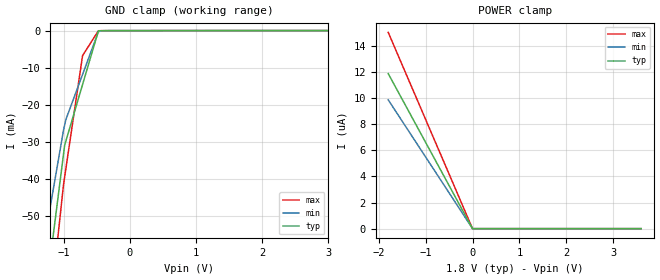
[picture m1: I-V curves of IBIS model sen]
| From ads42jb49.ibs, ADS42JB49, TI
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|   sen Model
[Model]   sen
Model_type   Input
Vinl = 0.4
Vinh = 1.2
|   typ   min   max
|   (nom PVT)   (fast PVT)   (slow PVT)
C_comp   1.286e-12   1.247e-12   1.328e-12
| Where nom  PVT is Nominal Process, 1.8V, 25C
|   Fast PVT is Strong Process,  1.9V, -40C
|   Slow PVT is Weak Process,   1.7V, 125C
[Voltage Range]   1.8   1.7   1.9
|Junction Temperature
[Temperature Range]   25   125   -40
[Power Clamp Reference]   1.8   1.7   1.9
[GND Clamp Reference]   0   0   0
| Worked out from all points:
|   GND clamp passes 1 mA (typ) near -0.49 V on its own axis
[GND Clamp]
|   Voltage   I(typ)   I(min)   I(max)
-1.8V     -820.9mA   -109.7mA   -1.727A
-1.49V    -102.4mA   -77.57mA   -123.3mA
-1.001V   -33.56mA   -27.01mA   -41.82mA
-982.8mV  -30.95mA   -25.49mA   -39.53mA
-965.6mV  -29.91mA   -24.08mA   -37.44mA
-712.5mV  -14.58mA   -11.87mA   -6.77mA
-473.1mV  -87.82uA   -310.1uA   -47uA
-280.5mV  -14.2uA    -14.49uA   -18.27uA
3.6V      0A         0A         0A
[POWER Clamp]
|   Voltage   I(typ)   I(min)   I(max)
-1.8V     11.89uA    9.877uA    15.05uA
-1.7mV    11.25nA    11.26nA    14.23nA
0V        0A         0A         0A
3.6V      0A         0A         0A
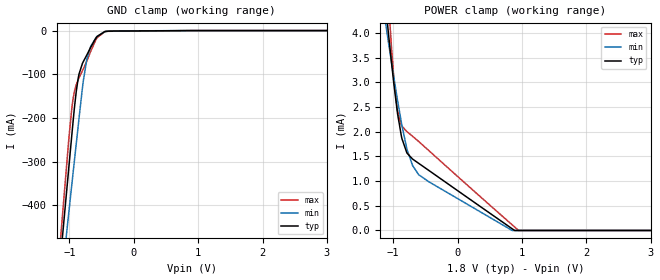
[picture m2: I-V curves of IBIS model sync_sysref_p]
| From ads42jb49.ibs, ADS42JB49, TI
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|   sync_sysref Model
[Model]   sync_sysref_p
Model_type   Input
Vinl = 0.5
Vinh = 1.3
|   typ   min   max
|   (nom PVT)   (fast PVT)   (slow PVT)
C_comp   1.431e-12   1.371e-12   1.487e-12
| Where nom  PVT is Nominal Process, 1.8V, 25C
|   Fast PVT is Strong Process,  1.9V, -40C
|   Slow PVT is Weak Process,   1.7V, 125C
[Voltage Range]   1.8   1.7   1.9
|Junction Temperature
[Temperature Range]   25   125   -40
[Power Clamp Reference]   1.8   1.7   1.9
[GND Clamp Reference]   0   0   0
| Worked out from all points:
|   GND clamp passes 1 mA (typ) near -0.18 V on its own axis
|   POWER clamp passes 1 mA (typ) near -0.21 V on its own axis
[GND Clamp]
|   Voltage   I(typ)   I(min)   I(max)
-1.8V     -1.605A    -1.53A     -1.676A
-1.195V   -611.2mA   -672.5mA   -577.9mA
-1.01V    -314mA     -416.5mA   -249.1mA
-941.4mV  -205.8mA   -323.5mA   -155mA
-894.6mV  -140.7mA   -260.2mA   -124.3mA
-863.3mV  -109.2mA   -218mA     -112.3mA
-786.8mV  -71.87mA   -118.2mA   -88.8mA
-730.7mV  -56.24mA   -66.69mA   -70.32mA
-669.5mV  -38.22mA   -36.27mA   -47.63mA
-586.8mV  -16.99mA   -16.1mA    -20.59mA
-450mV    -2.211mA   -2.6mA     -2.479mA
3.6V      0A         0A         0A
[POWER Clamp]
|   Voltage   I(typ)   I(min)   I(max)
-1.8V     13.87mA    10.45mA    22.16mA
-1.177V   5.343mA    4.728mA    7.007mA
-1.07V    3.957mA    3.791mA    4.608mA
-1.028V   3.429mA    3.426mA    3.747mA
-987.4mV  2.954mA    3.087mA    3.05mA
-929.6mV  2.351mA    2.62mA     2.41mA
-864mV    1.864mA    2.129mA    2.114mA
-788.4mV  1.578mA    1.664mA    2.006mA
-604.9mV  1.362mA    1.132mA    1.805mA
848.6mV   34.76uA    392.2nA    115uA
953.1mV   0A         0A         0A
3.6V      0A         0A         0A
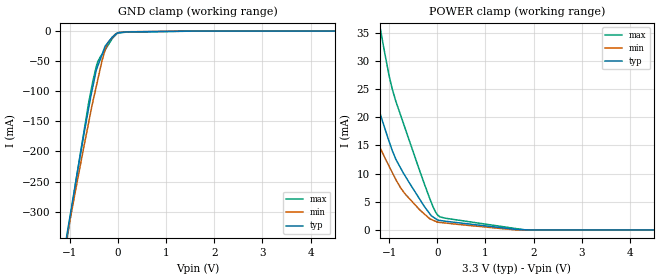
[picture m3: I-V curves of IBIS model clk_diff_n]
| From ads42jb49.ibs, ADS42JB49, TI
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[Model]   clk_diff_n
Model_type   Input
Vinl = 0.99
Vinh = 2.31
|   (nom PVT)   (fast PVT)   (slow PVT)
 C_comp   1.978e-12   1.903e-12   2.058e-12
|Where  nom  PVT is Nominal Process, 3.3V, 25C
|   Fast PVT is Strong Process,  3.45V, -40C
|   Slow PVT is Weak Process,   3.15V, 125C
[Model spec]
|subparameter   typ   min   max
Vinl   0.99   0.945   1.035
Vinh   2.31   2.205   2.415
[Voltage Range]   3.3   3.15   3.45
|Junction Temperature
[Temperature Range]   25   125   -40
[Power Clamp Reference]   3.3   3.15   3.45
[GND Clamp Reference]   0   0   0
[GND Clamp]
|   Voltage   I(typ)   I(min)   I(max)
-3.3V     -1.785A    -1.645A    -1.893A
-1.518V   -555.1mA   -536.1mA   -582.8mA
-861.3mV  -240.5mA   -254.1mA   -240.7mA
-621mV    -131.5mA   -155mA     -122.6mA
-527.9mV  -92.85mA   -117.9mA   -83.7mA
-452mV    -64.25mA   -90.76mA   -57.98mA
-333.9mV  -38.69mA   -48.81mA   -38.45mA
-270.6mV  -24.98mA   -31.29mA   -31.21mA
-211mV    -18.93mA   -19.15mA   -23.69mA
-113.9mV  -9.365mA   -10.17mA   -11.41mA
-39.41fV  -2.687mA   -2.734mA   -3.197mA
6.6V      0A         0A         0A
[POWER Clamp]
|   Voltage   I(typ)   I(min)   I(max)
-3.3V     78.93mA    53.76mA    139.8mA
-3.15V    74.76mA    50.97mA    132.4mA
-1.98V    42.25mA    29.17mA    74.55mA
-1.832V   38.17mA    26.41mA    67.23mA
-1.499V   29.02mA    20.22mA    50.98mA
-1.232V   21.76mA    15.33mA    37.9mA
-1.093V   18.07mA    12.85mA    31.37mA
-861.3mV  12.54mA    8.911mA    22.82mA
-365.4mV  5.451mA    3.563mA    10.48mA
-3.15mV   1.81mA     1.415mA    2.75mA
1.839V    32.5uA     0A         0A
6.6V      0A         0A         0A
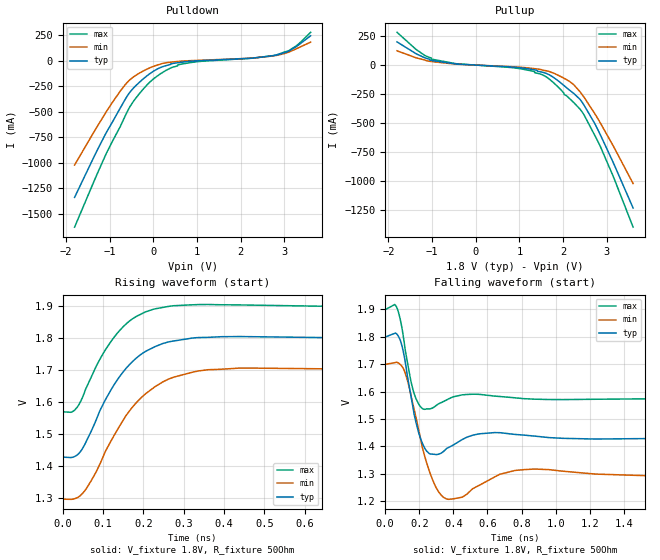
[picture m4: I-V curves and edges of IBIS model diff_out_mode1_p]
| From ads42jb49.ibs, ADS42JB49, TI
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|   diff_out_mode1 Model
[Model]   diff_out_mode1_p
Model_type   Output
Polarity   Non-Inverting
Vmeas = 1.622
Vref = 1.8
Cref = 0.5pF
Rref = 50
|   typ   min   max
|   (nom PVT)   (fast PVT)   (slow PVT)
C_comp   2.796e-12   2.332e-12   2.950e-12
[Model spec]
|subparameter   typ   min   max
Vmeas   1.622   1.52   1.7368
| Where nom  PVT is Nominal Process, 1.8V, 25C
|   Fast PVT is Strong Process,  1.9V, -40C
|   Slow PVT is Weak Process,   1.7V, 125C
[Voltage Range]   1.8   1.7   1.9
|Junction Temperature
[Temperature Range]   25   125   -40
[Pullup Reference]   1.8   1.7   1.9
[Pulldown Reference]   0   0   0
[Power Clamp Reference]   1.8   1.7   1.9
[GND Clamp Reference]   0   0   0
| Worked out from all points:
|   slope of the pulldown table from 0 to 0.27 V, typ, clamps not added: 5.06 ohm
|   slope of the pullup table from 0 to 0.27 V, typ, clamps not added: 49.4 ohm
|   falling waveform, V_fixture 1.8V, R_fixture 50Ohm: 20-80 % time 62.5ps typ, 86.6ps min, 53.8ps max; typ from 1.8 V to 1.43 V
|   rising waveform, V_fixture 1.8V, R_fixture 50Ohm: 20-80 % time 104ps typ, 118ps min, 93.6ps max; typ from 1.43 V to 1.8 V
[Pulldown]
|   Voltage   I(typ)   I(min)   I(max)
-1.8V     -1.339A    -1.022A    -1.631A
-1.084V   -711.4mA   -506.3mA   -917.2mA
-619.2mV  -362.5mA   -223.9mA   -520.4mA
-373.1mV  -233.8mA   -136mA     -352.5mA
-1.4mV    -104.7mA   -56.4mA    -180.4mA
316.5mV   -45.53mA   -18.59mA   -88.86mA
621mV     -16.47mA   -5.382mA   -35.66mA
2.252V    24.47mA    25mA       24.07mA
2.821V    55.2mA     51.92mA    56.97mA
3.103V    95.45mA    84.7mA     99.44mA
3.265V    136.7mA    115.3mA    143.4mA
3.6V      244.5mA    181.9mA    278mA
[Pullup]
|   Voltage   I(typ)   I(min)   I(max)
-1.8V     200.2mA    123.4mA    282.9mA
-1.352V   95.72mA    61.49mA    131.8mA
-1.015V   39.9mA     30.23mA    51.76mA
-450mV    9.4mA      7.851mA    11.89mA
1.082V    -26.42mA   -20.42mA   -36.05mA
1.345V    -41.54mA   -30.87mA   -56.55mA
1.694V    -86.38mA   -57.15mA   -124.5mA
2.154V    -218.9mA   -143.6mA   -291.8mA
2.475V    -344.9mA   -276.5mA   -428.6mA
2.842V    -595.7mA   -494.2mA   -695.6mA
3.172V    -864.6mA   -717mA     -986.8mA
3.6V      -1.235A    -1.023A    -1.4A
[Ramp]
R_load = 50
|   typ   min   max
dV/dt_r   0.100221/5.88979e-11   0.132023/7.44432e-11  0.0812183/4.87785e-11
dV/dt_f   0.223044/6.23591e-11   0.242156/8.6598e-11   0.197134/5.3486e-11
[Falling Waveform]
V_fixture = 1.8V
V_fixture_min = 1.7V
V_fixture_max = 1.9V
R_fixture = 50Ohm
|   Time   V(typ)   V(min)   V(max)
0s        1.799V     1.699V     1.899V
56ps      1.813V     1.706V     1.918V
92ps      1.781V     1.697V     1.852V
150ps     1.588V     1.589V     1.64V
202ps     1.439V     1.444V     1.549V
276ps     1.372V     1.281V     1.54V
360ps     1.392V     1.208V     1.57V
552ps     1.446V     1.258V     1.59V
812ps     1.441V     1.315V     1.574V
2.198ns   1.428V     1.296V     1.571V
[Rising Waveform]
V_fixture = 1.8V
V_fixture_min = 1.7V
V_fixture_max = 1.9V
R_fixture = 50Ohm
|   Time   V(typ)   V(min)   V(max)
0s        1.427V     1.295V     1.568V
30ps      1.429V     1.297V     1.574V
54ps      1.465V     1.321V     1.629V
108ps     1.611V     1.45V      1.766V
166ps     1.716V     1.572V     1.852V
200ps     1.753V     1.618V     1.877V
248ps     1.781V     1.661V     1.894V
336ps     1.8V       1.695V     1.903V
444ps     1.803V     1.705V     1.902V
1.8ns     1.798V     1.698V     1.899V
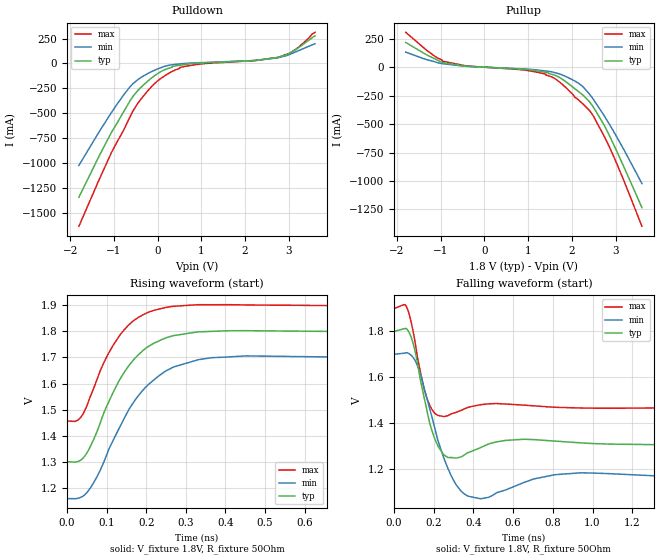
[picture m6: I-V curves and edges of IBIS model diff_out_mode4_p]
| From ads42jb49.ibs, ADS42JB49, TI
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|   diff_out_mode4 Model
[Model]   diff_out_mode4_p
Model_type   Output
Polarity   Non-Inverting
Vmeas = 1.565
Vref = 1.8
Cref = 0.5pF
Rref = 50
|   typ   min   max
|   (nom PVT)   (fast PVT)   (slow PVT)
C_comp   2.863e-12   2.367e-12   2.927e-12
[Model spec]
|subparameter   typ   min   max
Vmeas   1.565   1.465   1.685
| Where nom  PVT is Nominal Process, 1.8V, 25C
|   Fast PVT is Strong Process,  1.9V, -40C
|   Slow PVT is Weak Process,   1.7V, 125C
[Voltage Range]   1.8   1.7   1.9
|Junction Temperature
[Temperature Range]   25   125   -40
[Pullup Reference]   1.8   1.7   1.9
[Pulldown Reference]   0   0   0
[Power Clamp Reference]   1.8   1.7   1.9
[GND Clamp Reference]   0   0   0
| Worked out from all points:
|   slope of the pulldown table from 0 to 0.27 V, typ, clamps not added: 4.87 ohm
|   slope of the pullup table from 0 to 0.27 V, typ, clamps not added: 49.4 ohm
|   falling waveform, V_fixture 1.8V, R_fixture 50Ohm: 20-80 % time 69.6ps typ, 102ps min, 58.2ps max; typ from 1.8 V to 1.3 V
|   rising waveform, V_fixture 1.8V, R_fixture 50Ohm: 20-80 % time 102ps typ, 118ps min, 89.8ps max; typ from 1.3 V to 1.8 V
[Pulldown]
|   Voltage   I(typ)   I(min)   I(max)
-1.8V     -1.343A    -1.024A    -1.634A
-1.061V   -696.1mA   -496.5mA   -899.3mA
-783.5mV  -490.1mA   -320.6mA   -676mA
-610.2mV  -361.6mA   -224.8mA   -516.5mA
-373.1mV  -237mA     -139.3mA   -354.3mA
300uV     -101.9mA   -55.32mA   -175mA
333mV     -32.43mA   -13.29mA   -80.31mA
621mV     -11.39mA   -473.8uA   -30.46mA
2.252V    30.35mA    30.89mA    29.39mA
2.819V    72.47mA    63.9mA     67.36mA
3.173V    142.9mA    118.6mA    146.2mA
3.6V      277mA      197.8mA    312.4mA
[Pullup]
|   Voltage   I(typ)   I(min)   I(max)
-1.8V     217.1mA    132.2mA    306.5mA
-1.298V   103.6mA    63.77mA    141.1mA
-965.9mV  42.1mA     30.98mA    53.78mA
-450mV    10.25mA    8.157mA    13.33mA
1.082V    -26.37mA   -20.4mA    -35.98mA
1.397V    -44.75mA   -33.18mA   -60.73mA
1.722V    -92.16mA   -60.25mA   -132.7mA
2.154V    -215.6mA   -142.1mA   -289.1mA
2.493V    -352.2mA   -284.3mA   -431.1mA
2.732V    -506.6mA   -423.6mA   -603.8mA
2.911V    -644.8mA   -536.9mA   -746.5mA
3.6V      -1.234A    -1.023A    -1.398A
[Ramp]
R_load = 50
|   typ   min   max
dV/dt_r   0.119586/5.97826e-11   0.156071/7.40423e-11  0.0970831/4.79799e-11
dV/dt_f   0.297703/6.94567e-11   0.322276/1.01522e-10   0.263138/5.8084e-11
[Falling Waveform]
V_fixture = 1.8V
V_fixture_min = 1.7V
V_fixture_max = 1.9V
R_fixture = 50Ohm
|   Time   V(typ)   V(min)   V(max)
0s        1.799V     1.699V     1.899V
56ps      1.812V     1.705V     1.916V
86ps      1.776V     1.696V     1.842V
152ps     1.511V     1.551V     1.548V
202ps     1.338V     1.389V     1.445V
290ps     1.248V     1.165V     1.44V
376ps     1.27V      1.079V     1.468V
562ps     1.323V     1.106V     1.482V
940ps     1.312V     1.181V     1.465V
2.3ns     1.303V     1.162V     1.461V
[Rising Waveform]
V_fixture = 1.8V
V_fixture_min = 1.7V
V_fixture_max = 1.9V
R_fixture = 50Ohm
|   Time   V(typ)   V(min)   V(max)
0s        1.303V     1.162V     1.458V
34ps      1.308V     1.166V     1.471V
58ps      1.358V     1.2V       1.548V
108ps     1.54V      1.358V     1.725V
162ps     1.681V     1.516V     1.833V
198ps     1.734V     1.586V     1.868V
246ps     1.773V     1.645V     1.89V
334ps     1.798V     1.692V     1.902V
454ps     1.802V     1.706V     1.9V
1.8ns     1.799V     1.699V     1.899V
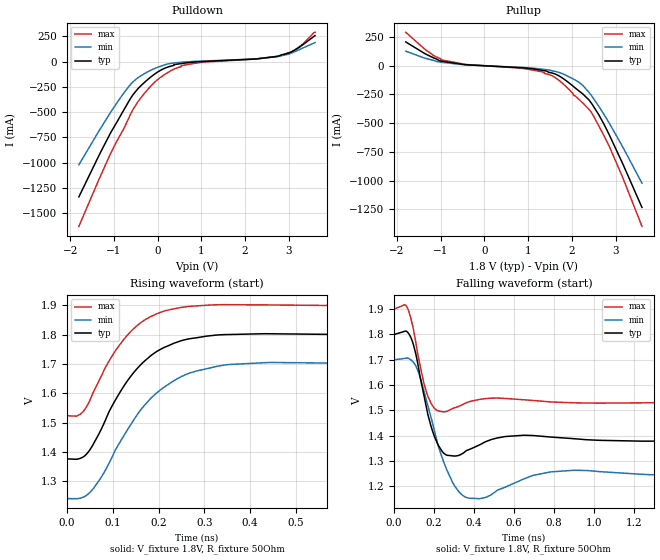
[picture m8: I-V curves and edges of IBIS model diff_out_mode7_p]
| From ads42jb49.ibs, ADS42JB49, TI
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|   diff_out_mode7 Model
[Model]   diff_out_mode7_p
Model_type   Output
Polarity   Non-Inverting
Vmeas = 1.599
Vref = 1.8
Cref = 0.5pF
Rref = 50
|   typ   min   max
|   (nom PVT)   (fast PVT)   (slow PVT)
C_comp   2.815e-12   2.354e-12   2.818e-12
[Model spec]
|subparameter   typ   min   max
Vmeas   1.599   1.498   1.7186
| Where nom  PVT is Nominal Process, 1.8V, 25C
|   Fast PVT is Strong Process,  1.9V, -40C
|   Slow PVT is Weak Process,   1.7V, 125C
[Voltage Range]   1.8   1.7   1.9
|Junction Temperature
[Temperature Range]   25   125   -40
[Pullup Reference]   1.8   1.7   1.9
[Pulldown Reference]   0   0   0
[Power Clamp Reference]   1.8   1.7   1.9
[GND Clamp Reference]   0   0   0
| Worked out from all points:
|   slope of the pulldown table from 0 to 0.27 V, typ, clamps not added: 4.97 ohm
|   slope of the pullup table from 0 to 0.27 V, typ, clamps not added: 49.4 ohm
|   falling waveform, V_fixture 1.8V, R_fixture 50Ohm: 20-80 % time 65.5ps typ, 93ps min, 55.6ps max; typ from 1.8 V to 1.38 V
|   rising waveform, V_fixture 1.8V, R_fixture 50Ohm: 20-80 % time 103ps typ, 118ps min, 91.9ps max; typ from 1.38 V to 1.8 V
[Pulldown]
|   Voltage   I(typ)   I(min)   I(max)
-1.8V     -1.341A    -1.023A    -1.632A
-1.082V   -711.8mA   -507.4mA   -917.2mA
-617.4mV  -363.6mA   -225.3mA   -521mA
-373.1mV  -235.1mA   -137.4mA   -353.4mA
20.08fV   -103.3mA   -55.85mA   -178.1mA
369mV     -31.78mA   -13.84mA   -75.35mA
621mV     -14.43mA   -3.408mA   -33.58mA
2.252V    26.68mA    27.26mA    26.11mA
2.842V    68.11mA    59.78mA    62.8mA
3.019V    88.51mA    78.83mA    91.79mA
3.229V    139.5mA    116.9mA    143.3mA
3.6V      257.6mA    188.7mA    290.9mA
[Pullup]
|   Voltage   I(typ)   I(min)   I(max)
-1.8V     207.4mA    127mA      291.5mA
-1.334V   99.81mA    62.88mA    135.5mA
-998.2mV  40.88mA    30.65mA    52.3mA
-450mV    9.603mA    7.918mA    12.22mA
1.082V    -26.4mA    -20.41mA   -36.03mA
1.364V    -42.72mA   -31.72mA   -58.17mA
1.7V      -87.57mA   -57.74mA   -126.2mA
2.154V    -217.5mA   -143mA     -290.8mA
2.479V    -345.6mA   -277.7mA   -427.8mA
2.858V    -606mA     -503.7mA   -706.3mA
3.18V     -870.3mA   -721.2mA   -992.5mA
3.6V      -1.234A    -1.023A    -1.399A
[Ramp]
R_load = 50
|   typ   min   max
dV/dt_r   0.108423/5.8938e-11   0.142735/7.37867e-11  0.0879367/4.77709e-11
dV/dt_f   0.252793/6.51883e-11   0.274288/9.27035e-11   0.223268/5.55748e-11
[Falling Waveform]
V_fixture = 1.8V
V_fixture_min = 1.7V
V_fixture_max = 1.9V
R_fixture = 50Ohm
|   Time   V(typ)   V(min)   V(max)
0s        1.799V     1.699V     1.899V
54ps      1.812V     1.705V     1.917V
86ps      1.785V     1.699V     1.859V
152ps     1.552V     1.57V      1.6V
200ps     1.402V     1.428V     1.51V
262ps     1.324V     1.27V      1.495V
362ps     1.341V     1.156V     1.53V
558ps     1.397V     1.197V     1.547V
902ps     1.388V     1.263V     1.53V
2.258ns   1.378V     1.242V     1.527V
[Rising Waveform]
V_fixture = 1.8V
V_fixture_min = 1.7V
V_fixture_max = 1.9V
R_fixture = 50Ohm
|   Time   V(typ)   V(min)   V(max)
0s        1.377V     1.242V     1.524V
32ps      1.381V     1.244V     1.533V
56ps      1.423V     1.273V     1.599V
80ps      1.495V     1.328V     1.676V
106ps     1.578V     1.408V     1.746V
162ps     1.699V     1.546V     1.842V
234ps     1.771V     1.644V     1.888V
326ps     1.799V     1.692V     1.902V
446ps     1.803V     1.705V     1.901V
1.4ns     1.798V     1.698V     1.899V
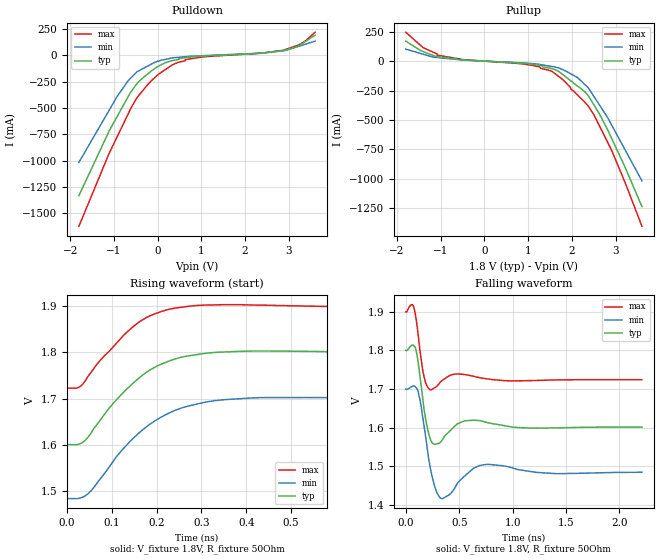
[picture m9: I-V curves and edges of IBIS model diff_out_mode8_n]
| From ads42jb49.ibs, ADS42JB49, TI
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[Model]   diff_out_mode8_n
Model_type   Output
Polarity   Non-Inverting
Vmeas = 1.707
Vref = 1.8
Cref = 0.5pF
Rref = 50
|   typ   min   max
|   (nom PVT)   (fast PVT)   (slow PVT)
C_comp   2.522e-12   2.302e-12   2.751e-12
[Model spec]
|subparameter   typ   min   max
Vmeas   1.707   1.606   1.806
| Where nom  PVT is Nominal Process, 1.8V, 25C
|   Fast PVT is Strong Process,  1.9V, -40C
|   Slow PVT is Weak Process,   1.7V, 125C
[Voltage Range]   1.8   1.7   1.9
[Temperature Range]   25   125   -40
[Pullup Reference]   1.8   1.7   1.9
[Pulldown Reference]   0   0   0
[Power Clamp Reference]   1.8   1.7   1.9
[GND Clamp Reference]   0   0   0
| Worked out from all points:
|   slope of the pulldown table from 0 to 0.27 V, typ, clamps not added: 5.4 ohm
|   slope of the pullup table from 0 to 0.27 V, typ, clamps not added: 49.4 ohm
|   falling waveform, V_fixture 1.8V, R_fixture 50Ohm: 20-80 % time 54.5ps typ, 67.2ps min, 47.9ps max; typ from 1.8 V to 1.6 V
|   rising waveform, V_fixture 1.8V, R_fixture 50Ohm: 20-80 % time 117ps typ, 128ps min, 103ps max; typ from 1.6 V to 1.8 V
[Pulldown]
|   Voltage   I(typ)   I(min)   I(max)
-1.8V     -1.332A    -1.017A    -1.623A
-1.11V    -720.8mA   -522.6mA   -932.2mA
-921.4mV  -578.2mA   -388mA     -770.1mA
-630mV    -360.2mA   -221.7mA   -519.2mA
-473.1mV  -269.2mA   -156.7mA   -403.7mA
-231.8mV  -178.3mA   -103.2mA   -280.4mA
11.97fV   -108.2mA   -57.48mA   -187.2mA
334.4mV   -50.6mA    -24.8mA    -91.31mA
632.7mV   -23.1mA    -13.1mA    -42.24mA
2.867V    45.49mA    43.39mA    47.29mA
3.213V    87.17mA    83.77mA    95.24mA
3.6V      191.1mA    134.1mA    218.5mA
[Pullup]
|   Voltage   I(typ)   I(min)   I(max)
-1.8V     170mA      102.2mA    245.2mA
-1.406V   81.95mA    59.19mA    115.2mA
-1.081V   39.54mA    30.23mA    50.84mA
-473.1mV  9.778mA    8.239mA    12.23mA
1.146V    -30.52mA   -23.01mA   -40.64mA
1.55V     -64.36mA   -45.45mA   -88.57mA
1.796V    -115.5mA   -73.12mA   -158.8mA
2.125V    -211.8mA   -139.3mA   -287mA
2.362V    -288.7mA   -222.8mA   -377.8mA
2.5V      -370.3mA   -299.4mA   -455.3mA
2.905V    -654.6mA   -541.9mA   -757mA
3.6V      -1.237A    -1.018A    -1.404A
[Ramp]
R_load = 50
|   typ   min   max
dV/dt_r   0.0649191/7.51387e-11  0.0842193/9.2168e-11   0.0524826/6.48584e-11
dV/dt_f   0.118972/5.40691e-11   0.129264/6.71371e-11   0.105444/4.76743e-11
[Falling Waveform]
V_fixture = 1.8V
V_fixture_min = 1.7V
V_fixture_max = 1.9V
R_fixture = 50Ohm
|   Time   V(typ)   V(min)   V(max)
0s        1.8V       1.7V       1.9V
64ps      1.814V     1.708V     1.918V
112ps     1.777V     1.696V     1.85V
166ps     1.659V     1.613V     1.738V
216ps     1.583V     1.516V     1.701V
274ps     1.557V     1.445V     1.704V
338ps     1.567V     1.416V     1.722V
550ps     1.618V     1.474V     1.738V
760ps     1.613V     1.505V     1.726V
2.21ns    1.601V     1.484V     1.724V
[Rising Waveform]
V_fixture = 1.8V
V_fixture_min = 1.7V
V_fixture_max = 1.9V
R_fixture = 50Ohm
|   Time   V(typ)   V(min)   V(max)
0s        1.601V     1.484V     1.723V
26ps      1.601V     1.484V     1.724V
48ps      1.618V     1.495V     1.75V
110ps     1.697V     1.574V     1.82V
144ps     1.73V      1.61V      1.853V
178ps     1.758V     1.64V      1.876V
242ps     1.786V     1.675V     1.896V
328ps     1.8V       1.695V     1.903V
442ps     1.803V     1.702V     1.902V
2ns       1.799V     1.699V     1.899V
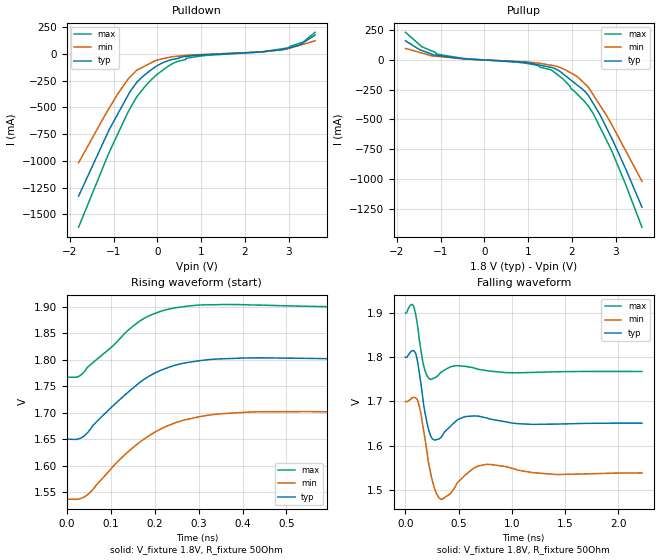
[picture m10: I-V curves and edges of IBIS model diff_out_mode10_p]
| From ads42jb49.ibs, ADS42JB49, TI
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|   diff_out_mode10 Model
[Model]   diff_out_mode10_p
Model_type   Output
Polarity   Non-Inverting
Vmeas = 1.729
Vref = 1.8
Cref = 0.5pF
Rref = 50
|   typ   min   max
|   (nom PVT)   (fast PVT)   (slow PVT)
C_comp   2.469e-12   2.315e-12   2.557e-12
[Model spec]
|subparameter   typ   min   max
Vmeas   1.729   1.629   1.828
| Where nom  PVT is Nominal Process, 1.8V, 25C
|   Fast PVT is Strong Process,  1.9V, -40C
|   Slow PVT is Weak Process,   1.7V, 125C
[Voltage Range]   1.8   1.7   1.9
[Temperature Range]   25   125   -40
[Pullup Reference]   1.8   1.7   1.9
[Pulldown Reference]   0   0   0
[Power Clamp Reference]   1.8   1.7   1.9
[GND Clamp Reference]   0   0   0
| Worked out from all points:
|   slope of the pulldown table from 0 to 0.27 V, typ, clamps not added: 5.56 ohm
|   slope of the pullup table from 0 to 0.27 V, typ, clamps not added: 49.4 ohm
|   falling waveform, V_fixture 1.8V, R_fixture 50Ohm: 20-80 % time 52.5ps typ, 62.9ps min, 47.9ps max; typ from 1.8 V to 1.65 V
|   rising waveform, V_fixture 1.8V, R_fixture 50Ohm: 20-80 % time 124ps typ, 133ps min, 108ps max; typ from 1.65 V to 1.8 V
[Pulldown]
|   Voltage   I(typ)   I(min)   I(max)
-1.8V     -1.33A     -1.018A    -1.621A
-1.105V   -711.8mA   -510.8mA   -924.5mA
-914.6mV  -569mA     -379.4mA   -757.4mA
-633.6mV  -358.7mA   -219.2mA   -517.1mA
-473.1mV  -266.3mA   -153.7mA   -401.8mA
11.97fV   -109.5mA   -57.89mA   -189.6mA
334.4mV   -52.57mA   -26.56mA   -93.24mA
653.6mV   -23.86mA   -14.23mA   -42.66mA
2.378V    18.16mA    18.35mA    18.4mA
3.011V    56.92mA    51.99mA    57.93mA
3.329V    105mA      90mA       110.3mA
3.6V      176.2mA    122.5mA    201.7mA
[Pullup]
|   Voltage   I(typ)   I(min)   I(max)
-1.8V     161.2mA    96.99mA    232.2mA
-1.427V   79.72mA    58.27mA    111.4mA
-1.102V   39.34mA    31.35mA    50.69mA
1.146V    -34.67mA   -23.03mA   -40.7mA
1.55V     -64.49mA   -45.58mA   -88.76mA
1.797V    -116.4mA   -73.72mA   -159.9mA
2.127V    -212.8mA   -140.5mA   -288.9mA
2.362V    -290.6mA   -223.6mA   -380.1mA
2.495V    -369.8mA   -296.8mA   -454.8mA
2.909V    -658.1mA   -542.2mA   -763.1mA
3.22V     -908.7mA   -757.3mA   -1.039A
3.6V      -1.237A    -1.019A    -1.406A
[Ramp]
R_load = 50
|   typ   min   max
dV/dt_r   0.0520591/8.84295e-11  0.0670053/1.03585e-10   0.042083/7.60243e-11
dV/dt_f   0.0892259/5.23103e-11  0.0969698/6.26077e-11   0.0791552/4.76008e-11
[Falling Waveform]
V_fixture = 1.8V
V_fixture_min = 1.7V
V_fixture_max = 1.9V
R_fixture = 50Ohm
|   Time   V(typ)   V(min)   V(max)
0s        1.8V       1.7V       1.9V
66ps      1.815V     1.708V     1.919V
116ps     1.787V     1.701V     1.867V
172ps     1.691V     1.633V     1.78V
222ps     1.632V     1.554V     1.752V
278ps     1.613V     1.499V     1.754V
332ps     1.618V     1.479V     1.766V
492ps     1.659V     1.517V     1.781V
764ps     1.662V     1.558V     1.77V
2.222ns   1.651V     1.538V     1.768V
[Rising Waveform]
V_fixture = 1.8V
V_fixture_min = 1.7V
V_fixture_max = 1.9V
R_fixture = 50Ohm
|   Time   V(typ)   V(min)   V(max)
0s        1.65V      1.537V     1.767V
26ps      1.651V     1.537V     1.768V
46ps      1.661V     1.545V     1.785V
68ps      1.683V     1.565V     1.8V
126ps     1.729V     1.616V     1.844V
184ps     1.767V     1.655V     1.881V
248ps     1.79V      1.682V     1.898V
334ps     1.801V     1.697V     1.903V
542ps     1.803V     1.702V     1.901V
2.028ns   1.799V     1.699V     1.899V
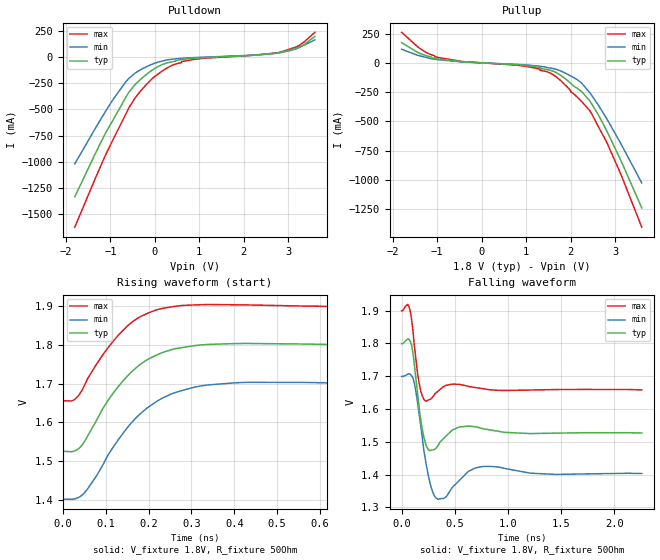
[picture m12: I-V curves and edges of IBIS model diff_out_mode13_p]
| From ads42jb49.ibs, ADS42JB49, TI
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|   diff_out_mode13 Model
[Model]   diff_out_mode13_p
Model_type   Output
Polarity   Non-Inverting
Vmeas = 1.669
Vref = 1.8
Cref = 0.5pF
Rref = 50
|   typ   min   max
|   (nom PVT)   (fast PVT)   (slow PVT)
C_comp   2.622e-12   2.308e-12   2.859e-12
[Model spec]
Vmeas   1.669   1.5647   1.7799
| Where nom  PVT is Nominal Process, 1.8V, 25C
|   Fast PVT is Strong Process,  1.9V, -40C
|   Slow PVT is Weak Process,   1.7V, 125C
[Voltage Range]   1.8   1.7   1.9
|Junction Temperature
[Temperature Range]   25   125   -40
[Pullup Reference]   1.8   1.7   1.9
[Pulldown Reference]   0   0   0
[Power Clamp Reference]   1.8   1.7   1.9
[GND Clamp Reference]   0   0   0
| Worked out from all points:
|   slope of the pulldown table from 0 to 0.27 V, typ, clamps not added: 5.18 ohm
|   slope of the pullup table from 0 to 0.27 V, typ, clamps not added: 49.4 ohm
|   falling waveform, V_fixture 1.8V, R_fixture 50Ohm: 20-80 % time 56.5ps typ, 74.6ps min, 49.1ps max; typ from 1.8 V to 1.53 V
|   rising waveform, V_fixture 1.8V, R_fixture 50Ohm: 20-80 % time 109ps typ, 121ps min, 98.2ps max; typ from 1.53 V to 1.8 V
[Pulldown]
|   Voltage   I(typ)   I(min)   I(max)
-1.8V     -1.337A    -1.021A    -1.627A
-1.087V   -709.6mA   -503.5mA   -916.9mA
-650.8mV  -382.3mA   -234.3mA   -543.8mA
-450mV    -264.1mA   -153.4mA   -393.3mA
-219.6mV  -174.8mA   -97.22mA   -274.3mA
300uV     -107mA     -56.82mA   -184.1mA
326.1mV   -48.6mA    -21.76mA   -90.44mA
621mV     -20.59mA   -9.358mA   -39.95mA
1.082V    -3.545mA   495.8uA    -10.47mA
2.83V     45.39mA    45.44mA    49.55mA
3.244V    95.25mA    93.3mA     112.5mA
3.6V      198.2mA    166.4mA    238.9mA
[Pullup]
|   Voltage   I(typ)   I(min)   I(max)
-1.8V     172.4mA    115.5mA    260.2mA
-1.383V   78.8mA     58.39mA    120.7mA
-1.057V   36.43mA    30mA       51.17mA
-450mV    9.274mA    7.812mA    11.62mA
1.005V    -22.93mA   -18.08mA   -31.08mA
1.303V    -39.18mA   -29.04mA   -53.26mA
1.694V    -87.01mA   -57.54mA   -125mA
2.154V    -218.9mA   -145mA     -294.2mA
2.474V    -349.7mA   -276.8mA   -433.7mA
2.827V    -591.8mA   -486.3mA   -689.8mA
3.167V    -863.2mA   -715.2mA   -985mA
3.6V      -1.237A    -1.024A    -1.402A
[Ramp]
R_load = 50
|   typ   min   max
dV/dt_r   0.081567/6.36548e-11   0.106769/8.02924e-11  0.0660026/5.64253e-11
dV/dt_f   0.163592/5.61906e-11   0.177711/7.3995e-11   0.14479/4.88344e-11
[Falling Waveform]
V_fixture = 1.8V
V_fixture_min = 1.7V
V_fixture_max = 1.9V
R_fixture = 50Ohm
|   Time   V(typ)   V(min)   V(max)
0s        1.799V     1.699V     1.899V
56ps      1.813V     1.706V     1.919V
92ps      1.796V     1.702V     1.876V
150ps     1.647V     1.618V     1.708V
208ps     1.515V     1.476V     1.63V
278ps     1.474V     1.36V      1.631V
342ps     1.488V     1.324V     1.654V
544ps     1.545V     1.382V     1.675V
768ps     1.539V     1.425V     1.662V
2.258ns   1.527V     1.403V     1.658V
[Rising Waveform]
V_fixture = 1.8V
V_fixture_min = 1.7V
V_fixture_max = 1.9V
R_fixture = 50Ohm
|   Time   V(typ)   V(min)   V(max)
0s        1.526V     1.403V     1.657V
28ps      1.527V     1.403V     1.659V
52ps      1.553V     1.421V     1.698V
76ps      1.6V       1.458V     1.745V
112ps     1.667V     1.527V     1.801V
170ps     1.74V      1.611V     1.865V
232ps     1.78V      1.663V     1.893V
322ps     1.799V     1.694V     1.903V
430ps     1.803V     1.703V     1.902V
1.414ns   1.799V     1.698V     1.899V
